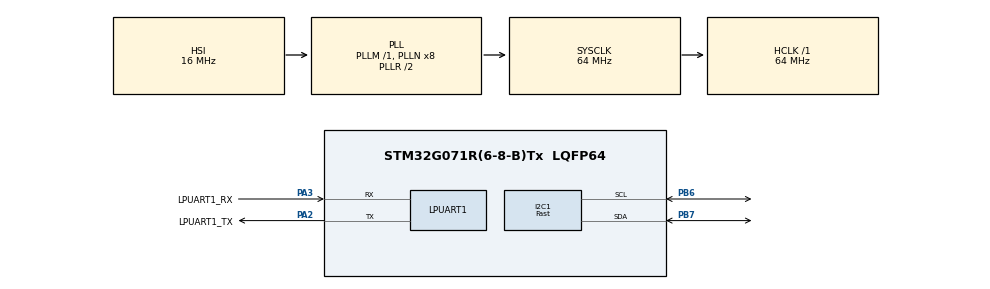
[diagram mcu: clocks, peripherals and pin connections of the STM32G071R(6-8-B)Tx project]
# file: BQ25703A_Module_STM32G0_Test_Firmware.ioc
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Dma.I2C1_RX.1.Direction=DMA_PERIPH_TO_MEMORY
Dma.I2C1_RX.1.EventEnable=DISABLE
Dma.I2C1_RX.1.Instance=DMA1_Channel5
Dma.I2C1_RX.1.MemDataAlignment=DMA_MDATAALIGN_BYTE
Dma.I2C1_RX.1.MemInc=DMA_MINC_ENABLE
Dma.I2C1_RX.1.Mode=DMA_NORMAL
Dma.I2C1_RX.1.PeriphDataAlignment=DMA_PDATAALIGN_BYTE
Dma.I2C1_RX.1.PeriphInc=DMA_PINC_DISABLE
Dma.I2C1_RX.1.Polarity=HAL_DMAMUX_REQ_GEN_RISING
Dma.I2C1_RX.1.Priority=DMA_PRIORITY_HIGH
Dma.I2C1_RX.1.RequestNumber=1
Dma.I2C1_RX.1.SignalID=NONE
Dma.I2C1_RX.1.SyncEnable=DISABLE
Dma.I2C1_RX.1.SyncPolarity=HAL_DMAMUX_SYNC_NO_EVENT
Dma.I2C1_RX.1.SyncRequestNumber=1
Dma.I2C1_RX.1.SyncSignalID=NONE
Dma.I2C1_TX.0.Direction=DMA_MEMORY_TO_PERIPH
Dma.I2C1_TX.0.EventEnable=DISABLE
Dma.I2C1_TX.0.Instance=DMA1_Channel4
Dma.I2C1_TX.0.MemDataAlignment=DMA_MDATAALIGN_BYTE
Dma.I2C1_TX.0.MemInc=DMA_MINC_ENABLE
Dma.I2C1_TX.0.Mode=DMA_NORMAL
Dma.I2C1_TX.0.PeriphDataAlignment=DMA_PDATAALIGN_BYTE
Dma.I2C1_TX.0.PeriphInc=DMA_PINC_DISABLE
Dma.I2C1_TX.0.Polarity=HAL_DMAMUX_REQ_GEN_RISING
Dma.I2C1_TX.0.Priority=DMA_PRIORITY_HIGH
Dma.I2C1_TX.0.RequestNumber=1
Dma.I2C1_TX.0.SignalID=NONE
Dma.I2C1_TX.0.SyncEnable=DISABLE
Dma.I2C1_TX.0.SyncPolarity=HAL_DMAMUX_SYNC_NO_EVENT
Dma.I2C1_TX.0.SyncRequestNumber=1
Dma.I2C1_TX.0.SyncSignalID=NONE
Dma.Request0=I2C1_TX
Dma.Request1=I2C1_RX
FREERTOS.Tasks01=defaultTask,0,128,StartDefaultTask,Default,NULL
I2C1.I2C_Speed_Mode=I2C_Fast
I2C1.Timing=0x00602173
Mcu.Family=STM32G0
Mcu.Name=STM32G071R(6-8-B)Tx
Mcu.Package=LQFP64
NVIC.DMA1_Ch4_7_DMAMUX1_OVR_IRQn=true\:0\:0\:false\:false\:true\:false\:false\:true
NVIC.I2C1_IRQn=true\:3\:0\:false\:false\:true\:true\:true\:true
NVIC.TIM2_IRQn=true\:0\:0\:false\:false\:true\:false\:false\:true
NVIC.TimeBase=TIM2_IRQn
NVIC.TimeBaseIP=TIM2
PA13.GPIO_Label=TMS
PA13.Mode=Serial_Wire
PA13.Signal=SYS_SWDIO
PA14-BOOT0.GPIO_Label=TCK
PA14-BOOT0.Mode=Serial_Wire
PA14-BOOT0.Signal=SYS_SWCLK
PA2.GPIO_Label=LPUART1_TX
PA2.Mode=Asynchronous
PA2.Signal=LPUART1_TX
PA3.GPIO_Label=LPUART1_RX
PA3.Mode=Asynchronous
PA3.Signal=LPUART1_RX
PB6.Mode=I2C
PB6.Signal=I2C1_SCL
PB7.Mode=I2C
PB7.Signal=I2C1_SDA
PC13.Mode=SYS_WakeUp1
PC13.Signal=SYS_WKUP2
PC14-OSC32_IN\ (PC14).Mode=LSE-External-Oscillator
PC14-OSC32_IN\ (PC14).Signal=RCC_OSC32_IN
PC15-OSC32_OUT\ (PC15).Mode=LSE-External-Oscillator
PC15-OSC32_OUT\ (PC15).Signal=RCC_OSC32_OUT
PF0-OSC_IN\ (PF0).GPIO_Label=MCO
PF0-OSC_IN\ (PF0).Mode=HSE-External-Clock-Source
PF0-OSC_IN\ (PF0).Signal=RCC_OSC_IN
ProjectManager.HeapSize=0x200
ProjectManager.StackSize=0x400
ProjectManager.TargetToolchain=TrueSTUDIO
RCC.ADCFreq_Value=64000000
RCC.AHBFreq_Value=64000000
RCC.CortexFreq_Value=64000000
RCC.EXTERNAL_CLOCK_VALUE=12288000
RCC.HCLKFreq_Value=64000000
RCC.HSE_VALUE=8000000
RCC.HSI_VALUE=16000000
RCC.SYSCLKFreq_VALUE=64000000
RCC.SYSCLKSource=RCC_SYSCLKSOURCE_PLLCLK
RCC.VCOOutputFreq_Value=128000000
VP_FREERTOS_VS_CMSIS_V1.Mode=CMSIS_V1
VP_SYS_VS_tim2.Mode=TIM2
board=NUCLEO-G071RB

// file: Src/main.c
/* USER CODE BEGIN Header */
/**
  ******************************************************************************
  * @file           : main.c
  * @brief          : Main program body
  ******************************************************************************
  * @attention
  *
  * <h2><center>&copy; Copyright (c) 2019 STMicroelectronics.
  * All rights reserved.</center></h2>
  *
  * This software component is licensed by ST under BSD 3-Clause license,
  * the "License"; You may not use this file except in compliance with the
  * License. You may obtain a copy of the License at:
  *                        opensource.org/licenses/BSD-3-Clause
  *
  ******************************************************************************
  */
/* USER CODE END Header */

#include "main.h"
#include "cmsis_os.h"

/* USER CODE BEGIN Includes */

#include "bq25703a_regulator.h"

/* USER CODE END Includes */

I2C_HandleTypeDef hi2c1;
DMA_HandleTypeDef hdma_i2c1_tx;
DMA_HandleTypeDef hdma_i2c1_rx;

UART_HandleTypeDef hlpuart1;

osThreadId defaultTaskHandle;
/* USER CODE BEGIN PV */

SemaphoreHandle_t xTxMutex_Regulator;

/* USER CODE END PV */

void SystemClock_Config(void);
static void MX_GPIO_Init(void);
static void MX_DMA_Init(void);
static void MX_I2C1_Init(void);
static void MX_LPUART1_UART_Init(void);
void StartDefaultTask(void const * argument);

int main(void)
{

  /* MCU Configuration--------------------------------------------------------*/

  /* Reset of all peripherals, Initializes the Flash interface and the Systick. */
  HAL_Init();

  /* Configure the system clock */
  SystemClock_Config();

  /* Initialize all configured peripherals */
  MX_GPIO_Init();
  MX_DMA_Init();
  MX_I2C1_Init();
  MX_LPUART1_UART_Init();

  /* USER CODE BEGIN RTOS_MUTEX */

	xTxMutex_Regulator = xSemaphoreCreateMutex();
	configASSERT(xTxMutex_Regulator);

  /* USER CODE END RTOS_MUTEX */

  /* Create the thread(s) */
  /* definition and creation of defaultTask */
  osThreadDef(defaultTask, StartDefaultTask, osPriorityNormal, 0, 128);
  defaultTaskHandle = osThreadCreate(osThread(defaultTask), NULL);

  /* USER CODE BEGIN RTOS_THREADS */

	/* Start the task that manages the regulator*/
	osThreadDef(regulator, vRegulator, REGULATOR_TASK_PRIORITY, 0, vRegulator_STACK_SIZE);
	regulatorTaskHandle = osThreadCreate(osThread(regulator), NULL);

  /* USER CODE END RTOS_THREADS */

  /* Start scheduler */
  osKernelStart();

  /* We should never get here as control is now taken by the scheduler */

  /* Infinite loop */
  while (1)
  {

  }
}

void SystemClock_Config(void)
{
  RCC_OscInitTypeDef RCC_OscInitStruct = {0};
  RCC_ClkInitTypeDef RCC_ClkInitStruct = {0};
  RCC_PeriphCLKInitTypeDef PeriphClkInit = {0};

  /** Configure the main internal regulator output voltage
  */
  HAL_PWREx_ControlVoltageScaling(PWR_REGULATOR_VOLTAGE_SCALE1);
  /** Initializes the CPU, AHB and APB busses clocks
  */
  RCC_OscInitStruct.OscillatorType = RCC_OSCILLATORTYPE_HSI;
  RCC_OscInitStruct.HSIState = RCC_HSI_ON;
  RCC_OscInitStruct.HSIDiv = RCC_HSI_DIV1;
  RCC_OscInitStruct.HSICalibrationValue = RCC_HSICALIBRATION_DEFAULT;
  RCC_OscInitStruct.PLL.PLLState = RCC_PLL_ON;
  RCC_OscInitStruct.PLL.PLLSource = RCC_PLLSOURCE_HSI;
  RCC_OscInitStruct.PLL.PLLM = RCC_PLLM_DIV1;
  RCC_OscInitStruct.PLL.PLLN = 8;
  RCC_OscInitStruct.PLL.PLLP = RCC_PLLP_DIV2;
  RCC_OscInitStruct.PLL.PLLQ = RCC_PLLQ_DIV2;
  RCC_OscInitStruct.PLL.PLLR = RCC_PLLR_DIV2;
  if (HAL_RCC_OscConfig(&RCC_OscInitStruct) != HAL_OK)
  {
    Error_Handler();
  }
  /** Initializes the CPU, AHB and APB busses clocks
  */
  RCC_ClkInitStruct.ClockType = RCC_CLOCKTYPE_HCLK|RCC_CLOCKTYPE_SYSCLK
                              |RCC_CLOCKTYPE_PCLK1;
  RCC_ClkInitStruct.SYSCLKSource = RCC_SYSCLKSOURCE_PLLCLK;
  RCC_ClkInitStruct.AHBCLKDivider = RCC_SYSCLK_DIV1;
  RCC_ClkInitStruct.APB1CLKDivider = RCC_HCLK_DIV1;

  if (HAL_RCC_ClockConfig(&RCC_ClkInitStruct, FLASH_LATENCY_2) != HAL_OK)
  {
    Error_Handler();
  }
  /** Initializes the peripherals clocks
  */
  PeriphClkInit.PeriphClockSelection = RCC_PERIPHCLK_LPUART1|RCC_PERIPHCLK_I2C1;
  PeriphClkInit.Lpuart1ClockSelection = RCC_LPUART1CLKSOURCE_PCLK1;
  PeriphClkInit.I2c1ClockSelection = RCC_I2C1CLKSOURCE_PCLK1;
  if (HAL_RCCEx_PeriphCLKConfig(&PeriphClkInit) != HAL_OK)
  {
    Error_Handler();
  }
}

static void MX_I2C1_Init(void)
{

  hi2c1.Instance = I2C1;
  hi2c1.Init.Timing = 0x10707DBC;
  hi2c1.Init.OwnAddress1 = 0;
  hi2c1.Init.AddressingMode = I2C_ADDRESSINGMODE_7BIT;
  hi2c1.Init.DualAddressMode = I2C_DUALADDRESS_DISABLE;
  hi2c1.Init.OwnAddress2 = 0;
  hi2c1.Init.OwnAddress2Masks = I2C_OA2_NOMASK;
  hi2c1.Init.GeneralCallMode = I2C_GENERALCALL_DISABLE;
  hi2c1.Init.NoStretchMode = I2C_NOSTRETCH_DISABLE;
  if (HAL_I2C_Init(&hi2c1) != HAL_OK)
  {
    Error_Handler();
  }
  /** Configure Analogue filter
  */
  if (HAL_I2CEx_ConfigAnalogFilter(&hi2c1, I2C_ANALOGFILTER_ENABLE) != HAL_OK)
  {
    Error_Handler();
  }
  /** Configure Digital filter
  */
  if (HAL_I2CEx_ConfigDigitalFilter(&hi2c1, 0) != HAL_OK)
  {
    Error_Handler();
  }

}

static void MX_LPUART1_UART_Init(void)
{

  hlpuart1.Instance = LPUART1;
  hlpuart1.Init.BaudRate = 209700;
  hlpuart1.Init.WordLength = UART_WORDLENGTH_7B;
  hlpuart1.Init.StopBits = UART_STOPBITS_1;
  hlpuart1.Init.Parity = UART_PARITY_NONE;
  hlpuart1.Init.Mode = UART_MODE_TX_RX;
  hlpuart1.Init.HwFlowCtl = UART_HWCONTROL_NONE;
  hlpuart1.Init.OneBitSampling = UART_ONE_BIT_SAMPLE_DISABLE;
  hlpuart1.Init.ClockPrescaler = UART_PRESCALER_DIV1;
  hlpuart1.AdvancedInit.AdvFeatureInit = UART_ADVFEATURE_NO_INIT;
  hlpuart1.FifoMode = UART_FIFOMODE_DISABLE;
  if (HAL_UART_Init(&hlpuart1) != HAL_OK)
  {
    Error_Handler();
  }
  if (HAL_UARTEx_SetTxFifoThreshold(&hlpuart1, UART_TXFIFO_THRESHOLD_1_8) != HAL_OK)
  {
    Error_Handler();
  }
  if (HAL_UARTEx_SetRxFifoThreshold(&hlpuart1, UART_RXFIFO_THRESHOLD_1_8) != HAL_OK)
  {
    Error_Handler();
  }
  if (HAL_UARTEx_DisableFifoMode(&hlpuart1) != HAL_OK)
  {
    Error_Handler();
  }

}

static void MX_DMA_Init(void)
{
  /* DMA controller clock enable */
  __HAL_RCC_DMA1_CLK_ENABLE();

  /* DMA interrupt init */
  /* DMA1_Ch4_7_DMAMUX1_OVR_IRQn interrupt configuration */
  HAL_NVIC_SetPriority(DMA1_Ch4_7_DMAMUX1_OVR_IRQn, 0, 0);
  HAL_NVIC_EnableIRQ(DMA1_Ch4_7_DMAMUX1_OVR_IRQn);

}

static void MX_GPIO_Init(void)
{

  /* GPIO Ports Clock Enable */
  __HAL_RCC_GPIOC_CLK_ENABLE();
  __HAL_RCC_GPIOF_CLK_ENABLE();
  __HAL_RCC_GPIOA_CLK_ENABLE();
  __HAL_RCC_GPIOB_CLK_ENABLE();

  GPIO_InitTypeDef GPIO_InitStruct = {0};

  /* GPIO Ports Clock Enable */
  __HAL_RCC_GPIOA_CLK_ENABLE();
  __HAL_RCC_GPIOB_CLK_ENABLE();
  __HAL_RCC_GPIOD_CLK_ENABLE();

  /*Configure GPIO pin Output Level */
  HAL_GPIO_WritePin(GPIOB, EN_OTG_Pin|ILIM_HIZ_Pin, GPIO_PIN_RESET);

  /*Configure GPIO pins : EN_OTG_Pin Red_LED_Pin ILIM_HIZ_Pin CELL_1S_DIS_EN_Pin
                           CELL_2S_DIS_EN_Pin CELL_3S_DIS_EN_Pin CELL_4S_DIS_EN_Pin */
  GPIO_InitStruct.Pin = EN_OTG_Pin|ILIM_HIZ_Pin;
  GPIO_InitStruct.Mode = GPIO_MODE_OUTPUT_PP;
  GPIO_InitStruct.Pull = GPIO_NOPULL;
  GPIO_InitStruct.Speed = GPIO_SPEED_FREQ_LOW;
  HAL_GPIO_Init(GPIOB, &GPIO_InitStruct);

  /*Configure GPIO pins : PROTCHOT_Pin CHRG_OK_Pin */
  GPIO_InitStruct.Pin = PROTCHOT_Pin|CHRG_OK_Pin;
  GPIO_InitStruct.Mode = GPIO_MODE_INPUT;
  GPIO_InitStruct.Pull = GPIO_NOPULL;
  HAL_GPIO_Init(GPIOB, &GPIO_InitStruct);

}

void StartDefaultTask(void const * argument)
{

  for(;;)
  {
    osDelay(1);
  }
}

void HAL_TIM_PeriodElapsedCallback(TIM_HandleTypeDef *htim)
{
  if (htim->Instance == TIM2) {
    HAL_IncTick();
  }
}

void Error_Handler(void)
{
}

/************************ (C) COPYRIGHT STMicroelectronics *****END OF FILE****/
